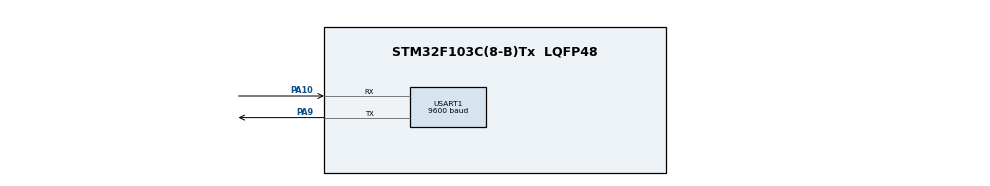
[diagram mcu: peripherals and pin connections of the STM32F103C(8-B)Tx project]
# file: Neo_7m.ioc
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Mcu.Family=STM32F1
Mcu.Name=STM32F103C(8-B)Tx
Mcu.Package=LQFP48
NVIC.PriorityGroup=NVIC_PRIORITYGROUP_4
PA10.Mode=Asynchronous
PA10.Signal=USART1_RX
PA13.Mode=Serial_Wire
PA13.Signal=SYS_JTMS-SWDIO
PA14.Mode=Serial_Wire
PA14.Signal=SYS_JTCK-SWCLK
PA9.Mode=Asynchronous
PA9.Signal=USART1_TX
ProjectManager.HeapSize=0x200
ProjectManager.StackSize=0x400
ProjectManager.TargetToolchain=STM32CubeIDE
RCC.APB1Freq_Value=8000000
RCC.APB2Freq_Value=8000000
USART1.BaudRate=9600
USART1.VirtualMode=VM_ASYNC
board=custom

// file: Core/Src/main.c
/* USER CODE BEGIN Header */
/**
  ******************************************************************************
  * @file           : main.c
  * @brief          : Main program body
  ******************************************************************************
  * @attention
  *
  * Copyright (c) 2025 STMicroelectronics.
  * All rights reserved.
  *
  * This software is licensed under terms that can be found in the LICENSE file
  * in the root directory of this software component.
  * If no LICENSE file comes with this software, it is provided AS-IS.
  *
  ******************************************************************************
  */
/* USER CODE END Header */
#include "main.h"

/* USER CODE BEGIN Includes */
#include <string.h>
/* USER CODE END Includes */

UART_HandleTypeDef huart1;

void SystemClock_Config(void);
static void MX_GPIO_Init(void);
static void MX_USART1_UART_Init(void);

int main(void)
{
  /* USER CODE BEGIN 1 */
  char msg[] = "Hello World!\r\n";
  /* USER CODE END 1 */

  /* MCU Configuration--------------------------------------------------------*/

  /* Reset of all peripherals, Initializes the Flash interface and the Systick. */
  HAL_Init();

  /* Configure the system clock */
  SystemClock_Config();

  /* Initialize all configured peripherals */
  MX_GPIO_Init();
  MX_USART1_UART_Init();

  /* Infinite loop */
  while (1)
  {

    /* USER CODE BEGIN 3 */
    HAL_UART_Transmit(&huart1, (uint8_t*)msg, strlen(msg), HAL_MAX_DELAY);
    HAL_Delay(1000); // 1 second delay
  }
  /* USER CODE END 3 */
}

void SystemClock_Config(void)
{
  RCC_OscInitTypeDef RCC_OscInitStruct = {0};
  RCC_ClkInitTypeDef RCC_ClkInitStruct = {0};

  /** Initializes the RCC Oscillators according to the specified parameters
  * in the RCC_OscInitTypeDef structure.
  */
  RCC_OscInitStruct.OscillatorType = RCC_OSCILLATORTYPE_HSI;
  RCC_OscInitStruct.HSIState = RCC_HSI_ON;
  RCC_OscInitStruct.HSICalibrationValue = RCC_HSICALIBRATION_DEFAULT;
  RCC_OscInitStruct.PLL.PLLState = RCC_PLL_ON;
  RCC_OscInitStruct.PLL.PLLSource = RCC_PLLSOURCE_HSI_DIV2;
  RCC_OscInitStruct.PLL.PLLMUL = RCC_PLL_MUL16;
  if (HAL_RCC_OscConfig(&RCC_OscInitStruct) != HAL_OK)
  {
    Error_Handler();
  }

  /** Initializes the CPU, AHB and APB buses clocks
  */
  RCC_ClkInitStruct.ClockType = RCC_CLOCKTYPE_HCLK|RCC_CLOCKTYPE_SYSCLK
                              |RCC_CLOCKTYPE_PCLK1|RCC_CLOCKTYPE_PCLK2;
  RCC_ClkInitStruct.SYSCLKSource = RCC_SYSCLKSOURCE_PLLCLK;
  RCC_ClkInitStruct.AHBCLKDivider = RCC_SYSCLK_DIV1;
  RCC_ClkInitStruct.APB1CLKDivider = RCC_HCLK_DIV2;
  RCC_ClkInitStruct.APB2CLKDivider = RCC_HCLK_DIV1;

  if (HAL_RCC_ClockConfig(&RCC_ClkInitStruct, FLASH_LATENCY_2) != HAL_OK)
  {
    Error_Handler();
  }
}

static void MX_USART1_UART_Init(void)
{

  huart1.Instance = USART1;
  huart1.Init.BaudRate = 115200;
  huart1.Init.WordLength = UART_WORDLENGTH_8B;
  huart1.Init.StopBits = UART_STOPBITS_1;
  huart1.Init.Parity = UART_PARITY_NONE;
  huart1.Init.Mode = UART_MODE_TX_RX;
  huart1.Init.HwFlowCtl = UART_HWCONTROL_NONE;
  huart1.Init.OverSampling = UART_OVERSAMPLING_16;
  if (HAL_UART_Init(&huart1) != HAL_OK)
  {
    Error_Handler();
  }

}

static void MX_GPIO_Init(void)
{
  GPIO_InitTypeDef GPIO_InitStruct = {0};

  /* GPIO Ports Clock Enable */
  __HAL_RCC_GPIOA_CLK_ENABLE();

  /*Configure GPIO pins : PA9 PA10 */
  GPIO_InitStruct.Pin = GPIO_PIN_9|GPIO_PIN_10;
  GPIO_InitStruct.Mode = GPIO_MODE_AF_PP;
  GPIO_InitStruct.Pull = GPIO_NOPULL;
  GPIO_InitStruct.Speed = GPIO_SPEED_FREQ_HIGH;
  HAL_GPIO_Init(GPIOA, &GPIO_InitStruct);

  /* USER CODE BEGIN MX_GPIO_Init_2 */
  /* Enable USART1 clock */
  __HAL_RCC_USART1_CLK_ENABLE();
  /* USER CODE END MX_GPIO_Init_2 */
}

void Error_Handler(void)
{
  __disable_irq();
  while (1)
  {
  }
}
